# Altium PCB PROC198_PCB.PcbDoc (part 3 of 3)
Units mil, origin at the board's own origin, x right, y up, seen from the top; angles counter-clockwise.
Board outline 858.22 x 1632.74 mil, 4 copper layers (Top Layer, L2_GND1, L3_PWR1, Bottom Layer), stack 54.546 mil thick; 116 components, 64 nets, 355 pads, 1018 vias.

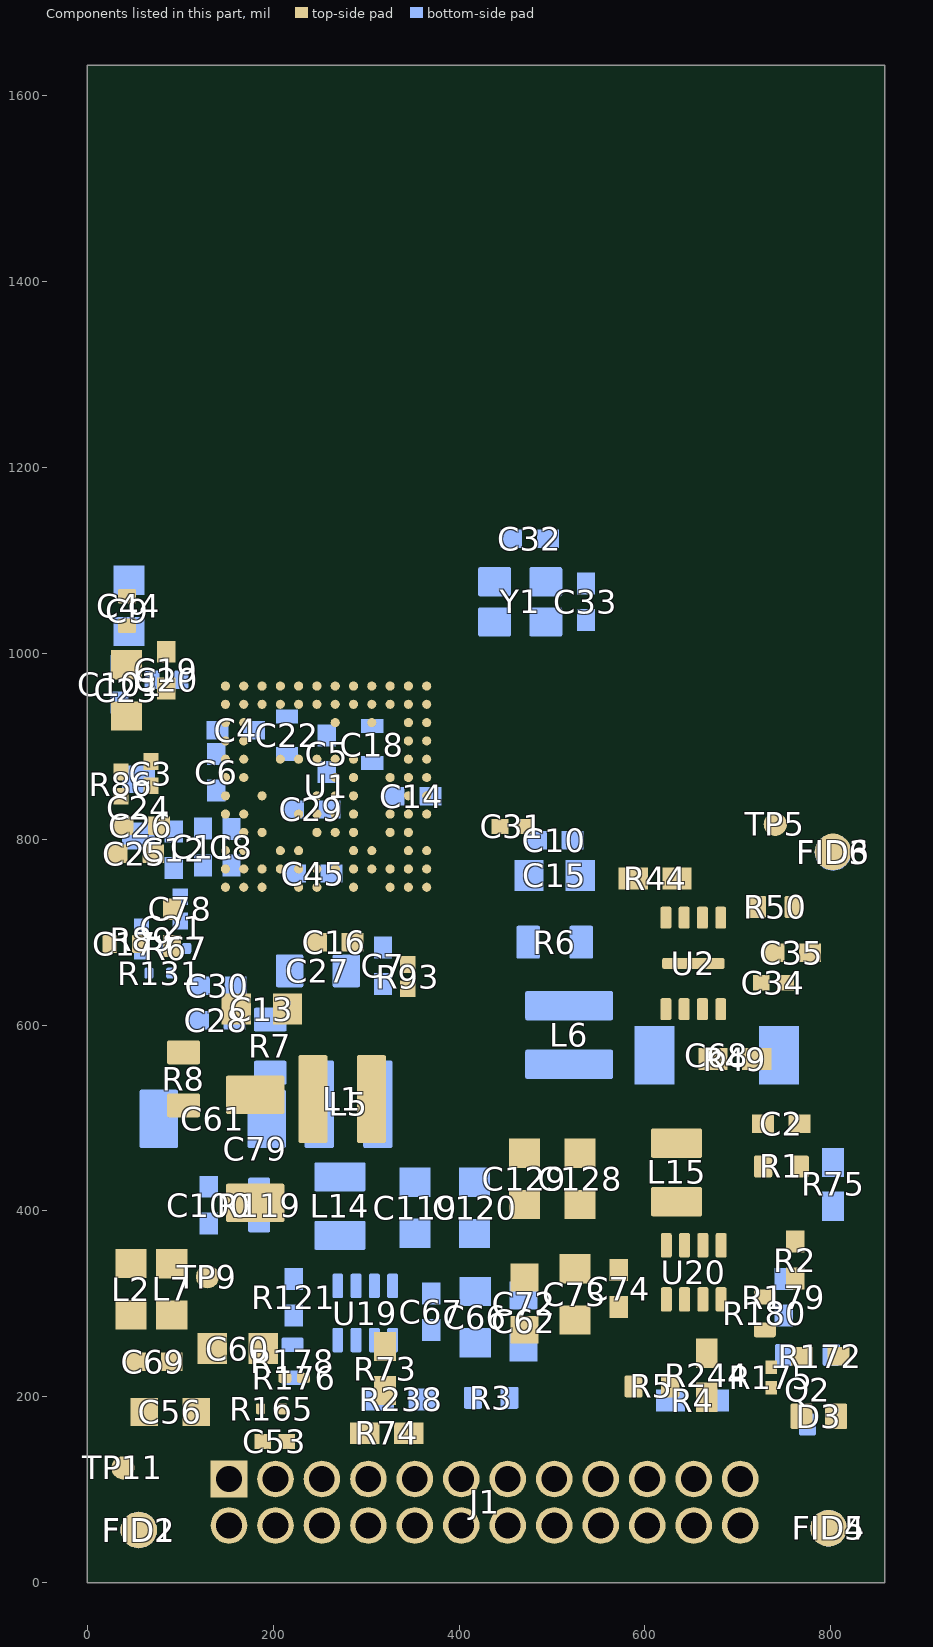
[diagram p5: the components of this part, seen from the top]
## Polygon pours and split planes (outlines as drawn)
RADAR_1V8 on L3_PWR1 "L6_SIGNAL 4-RADAR_1V8" (solid, remove dead copper, pour order 45094): 102.76,857.37 143.9,857.39 143.9,836.13 191.42,836.13 191.19,869.45 278.67,869.45 335.1,812.18 335.1,777.36 496.5,777.38 496.5,820.91 372.75,820.91 313.72,879.94 313.72,921.5 281.71,921.5 270.15,921.5 187.06,921.5 152.34,886.78 102.73,886.78
RADAR_3V3 on L3_PWR1 "RADAR_3V3_L03_P45183" (solid, pour order 45183): 45.3,333.44 45.3,142.85 677.97,142.85 720.43,185.31 720.43,197.8 685.54,198.1 102.68,197.81 89.44,211.06 89.44,336.33
INPUT_3V3 on L3_PWR1 "INPUT_3V3_L03_P45177" (solid, pour order 45177): 101.65,312.42 101.65,269.06 178.91,269.06 234.57,213.4 545.21,213.4 545.21,276.67 769.46,276.67 778.67,267.46 799.44,267.46 799.44,299.14 488.52,299.42 488.52,260 254.87,260 202.45,312.42
GND on L3_PWR1 "GND_L03_P45197" (solid, remove dead copper, pour order 45197): 145.2,679.64 -2.18,827.04 -3.26,825.95 -3.26,-6.44 861.73,-6.44 864.99,-3.18 863.9,-2.1 863.9,679.64
RADAR_1P2_RF on L3_PWR1 "RADAR_1P2_RF_L03_P45169" (solid, pour order 45169): 26.02,951.69 88.85,951.94 117.52,923.27 117.52,900.83 106.05,900.83 68.34,863.13 68.34,814.12 107.21,814.12 106.37,596.31 26.02,596.31
RADAR_1V2 on L3_PWR1 "RADAR_1V2_L03_P45154" (solid, pour order 45154): 82.72,847.61 117.73,847.61 145.54,818.03 201.49,818.03 200.98,867.16 244.66,867.16 244.66,846.88 257.74,833.8 307.39,832.96 314.27,826.08 314.27,717.27 117.73,717.27 119.25,809.17 99.65,828.77 82.72,828.77
RADAR_3V3 on L3_PWR1 "RADAR_3V3_L03_P45196" (solid, pour order 45196): 232.47,642.89 520.26,642.89 520.26,791.73 824.95,791.73 824.95,472.88 737.88,472.88 737.88,561.15 251.33,561.15
GND on L3_PWR1 "Top Layer-GND 4" (solid, remove dead copper, pour order 45082): 123.73,930.67 317.82,930.67 330.1,918.4 328.68,916.98 328.68,876.17 368.74,836.12 853.26,836.12 853.26,1642.81 2.07,1642.81 2.07,1052.34 106.29,948.12
RADAR_3V3 on L3_PWR1 "RADAR_3V3_L03_P45182" (solid, pour order 45182): 135.8,642.12 257.24,642.12 257.24,341 241.43,325.19 45.04,325.19 45.04,385 135.8,385
RADAR_1V2 on L3_PWR1 "RADAR_1V2_L03_P45200" (solid, pour order 45200): 182.5,729.65 116.75,729.65 116.75,668.65 182.5,668.65
RADAR_1V8 on L3_PWR1 "RADAR_1V8_L03_P45181" (solid, pour order 45181): 187.96,710.71 187.96,657 496.8,657 496.8,789.65 496.07,790.38 494.85,789.17 335.1,789.17 335.1,710.71
no net on Bottom Solder "NONET_L01_P-001" (solid): 864.93,1647.45 -2.48,1647.45 -3.34,1646.6 -3.34,1097.02 23.79,1070.7 24.09,1103.49 65.57,1103.49 65.39,1067.38 83.38,1049.39 83.27,988.15 118.44,988.15 118.44,950.2 136,932.64 199.87,932.9 199.87,945.43 229.38,945.43 229.56,932.9 327.04,932.9 329.31,930.64 329.24,877.8 340.97,866.31 383.61,866.31 399.27,850.64 412.64,850.83 424.13,839.28 865.43,839.28
REG_1V2 on Bottom Layer "REG_1V2_L04_P45186" (solid, pour order 45186): 170.48,563.04 222.4,563.04 270.07,563.04 270.07,466.32 270.65,465.74 169.78,465.46
GND on Bottom Layer "GND_L04_P45201" (solid, remove dead copper, pour order 45201): 841.13,821.58 840.02,822.7 2.38,822.7 -1.08,826.16 -2.17,825.08 -2.17,-7.32 862.82,-7.32 866.08,-4.06 865,-2.97 865,817.47
RADAR_1V2 on Bottom Layer "RADAR_1V2_L04_P45185" (solid, pour order 45185): 175.88,709.11 147.33,709.11 127.77,687.97 127.77,667.48 145.95,649.3 145.95,593.81 146.57,593.19 176.5,593.19 182.74,586.95 212.77,586.95 232.83,586.95 232.83,622.35 232.83,678.78 176.41,678.35
GND on Bottom Layer "GND_L04_P45195" (solid, pour order 45195): 268.69,676.76 269.49,677.56 295.91,677.56 295.91,663.15 302.05,657.01 331.67,657.01 331.67,576.42 330.33,575.08 330.07,575.35 283.9,575.35 283.9,614.85 272.42,626.32 268.42,626.32 268.42,677.83 267.62,678.63
RADAR_1P2_RF on Bottom Layer "RADAR_1P2_RF_L04_P45147" (solid, pour order 45147): 21.57,1040.44 65.07,1040.25 65.07,988.77 65.47,988.38 78.42,988.38 78.42,966.1 96.77,947.75 118.27,926.26 118.27,906.24 76.15,863.47 76.15,846.31 14.6,846.31 14.73,887.28 57.96,887.28 70.07,899.39 70.07,947.15 57.11,960.12 47.98,969.24 22.25,969.24
GND on Bottom Layer "Top Layer-GND 4" (solid, remove dead copper, pour order 44948): 31.53,1063.87 68.71,1064.02 83.26,1049.47 82.88,985.83 135.11,933.6 326.27,933.6 329.29,930.57 329.29,878.01 356.51,850.79 412.73,850.79 424.08,839.32 863.05,839.32 863.05,1641.25 -18.97,1641.25 -18.98,1113.78
REG_1V8 on Bottom Layer "REG_1V8_L04_P45190" (solid, pour order 45190): 514.81,708.38 549.2,708.4 548.78,672.32 633.53,672.32 633.53,534.94 585.86,534.94 585.86,589.31 574.97,600.2 463.89,600.2 463.41,600.69 463.41,638.92 511.57,638.92 514.31,641.66
INPUT_3V3 on Bottom Layer "INPUT_3V3_L04_P45193" (solid, pour order 45193): 102.45,307.82 161.25,307.82 161.36,307.29 161.36,269.08 160.72,269.08 150.58,258.94 150.58,156.18 151.11,156.18 176.73,130.56 176.73,84.57 223.68,84.57 223.68,41.67 223.04,42.1 128.7,42.1 128.7,127.27 97.86,158.11 97.86,307.82
RADAR_1V8 on Bottom Layer "RADAR_1V8_L04_P45152" (solid, pour order 45152): 497.7,651.8 497.9,828.46 351.77,828.46 341.41,838.82 341.41,854.23 326.38,869.25 295.37,869.25 295.37,851.09 310.43,836.03 320.09,836.03 354.72,801.4 396.75,802.62 424.09,775.28 424.09,652.59
GND on Bottom Layer "GND_L04_P45167" (solid, pour order 45167): 322.73,392.51 521.24,392.51 521.24,290.53 406.4,290.53 397.24,299.69 352.68,299.44 334.86,281.62 333.62,282.86 252.19,282.86 237.58,268.25 237.58,248.45 209.36,248.45 209.36,300.93 322.73,300.93 322.73,308.31
INPUT_3V3 on Bottom Layer "INPUT_3V3_L04_P45162" (solid, pour order 45162): 303.27,274.41 336.67,274.41 350.54,288.29 387.54,288.29 401.41,274.41 544.57,274.41 544.57,224.57 429.71,224.57 429.71,242.04 322.54,242.04 322.54,202.22 318.69,198.37 293.77,198.37 293.77,224.57 302.76,233.56 302.76,273.9
REG_OUT_1V8 on Bottom Layer "REG_OUT_1V8_L04_P45191" (solid, pour order 45191): 470.37,573.34 565.07,573.34 565.07,495.91 525.01,495.91 480.81,540.1 470.37,540.1
REG_OUT_1V2 on Bottom Layer "REG_OUT_1V2_L04_P45142" (solid, pour order 45142): 375.56,520.28 331.11,563.68 295.98,563.68 295.98,458.91 113.88,458.91 113.88,411.51 218.62,411.51 439.16,411.51 439.16,458.91 376.04,458.91
REG_RF_1V2 on Top Layer "REG_RF_1V2_L01_P45189" (solid, pour order 45189): 81.86,529.65 141.11,529.65 140.88,569.58 209.2,569.58 260.27,569.58 260.27,469.86 222.3,469.86 192.95,499.2 81.86,499.2
GND on Top Layer "GND_L01_P45199" (solid, remove dead copper, pour order 45199): 840.99,809.65 839.87,810.76 2.23,810.76 -1.23,814.22 -2.32,813.14 -2.32,-19.26 862.68,-19.26 865.94,-16 864.85,-14.91 864.85,805.53
RADAR_3V3 on Top Layer "RADAR_3V3_L01_P45194" (solid, pour order 45194): 131.86,319.47 21.62,319.47 21.62,381.07 10.01,395.83 10.26,697.29 35.48,697.29 35.48,676.76 23.96,676.76 23.28,399.07 36.22,385.19 89.97,384.58 89.97,381.07 131.86,339.18
RADAR_1V_RF_OUT on Top Layer "RADAR_1V_RF_OUT_L01_P45157" (solid, pour order 45157): 21.1,1038.12 66.42,1038.12 66.41,980.21 98.28,980.21 98.28,970.83 146.13,930.53 173.74,930.53 173.59,920.24 136.7,920.22 103.78,949.37 74.79,949.64 65.89,957 21.1,957
GND on Top Layer "Top Layer-GND 4" (solid, remove dead copper, pour order 45139): 81.35,1051.28 81.35,1019.94 135.16,966.14 135.16,950.79 148.35,937.56 170.51,937.66 174.01,934.16 187.7,934.16 189.83,932.04 324.92,932.04 324.92,876.14 337.26,863.8 337.19,847.05 343.21,841.03 352.38,841.03 353.48,842.13 353.48,854.78 416.64,854.72 432.79,838.56 849.47,838.56 849.47,1655.32 7.67,1655.32 7.66,1084.07 48.56,1084.07
INPUT_3V3 on Top Layer "INPUT_3V3_L01_P45192" (solid, pour order 45192): 22.92,307.85 161.48,307.85 161.48,269.57 151.03,259.13 151.03,155.79 177.46,129.36 177.46,85.04 224.34,85.04 226.68,82.7 226.68,42 130.79,42 128.45,44.34 128.45,128.49 94.35,162.58 94.35,206.71 73.9,227.17 74.75,228.02 74.75,262.97 68.15,269.57 22.5,269.57
RADAR_1P2_RF on Top Layer "Top Layer-RADAR_1P2_RF" (solid, remove dead copper, pour order 45126): 71.21,936.66 101.81,936.66 125.93,912.54 171.56,912.54 175.13,908.97 175.13,899.26 172.56,896.69 133.66,896.69 88.4,896.69 71.21,913.88
REG_OUT_1V8 on Top Layer "REG_OUT_1V8_L01_P44844" (solid, pour order 44844): 739.41,508.63 739.41,435.71 689.87,435.71 689.87,450.01 563.21,450.01 555.51,442.31 441.15,442.31 441.15,504.78 441.15,536.1 551.6,536.37 551.81,508.02
GND on Top Layer "GND_L01_P45160" (solid, pour order 45160): 773.65,296.71 773.13,297.23 773.13,332.32 709.18,332.32 699.79,341.71 629.29,341.71 629.29,348.8 628.4,349.68 628.4,377.14 627.34,378.2 595.63,378.2 547.8,426.03 426.66,426.03 426.66,313.22 702,313.22 702,304.96 709.89,297.07
RADAR_1P2_RF on Top Layer "RADAR_1P2_RF_L01_P45188" (solid, pour order 45188): 62.44,635.13 62.44,592.16 82.94,592.16 82.94,549.9 123.89,549.9 123.89,600.24 114.09,600.1 98.49,615.7 98.49,635.13
INPUT_3V3 on Top Layer "INPUT_3V3_L01_P45175" (solid, pour order 45175): 647.3,317.89 610.21,317.89 601.29,308.98 545.84,308.98 535.51,298.66 495.79,298.66 495.79,287.53 442.54,287.53 442.54,256.55 474.31,223.42 570.44,223.42 570.44,278.13 574.01,281.69 648.19,281.69 648.91,282.41 648.91,317.72
REG_OUT_1V2 on Top Layer "REG_OUT_1V2_L01_P45163" (solid, pour order 45163): 290.23,571.32 290.89,570.66 345.31,570.66 345.31,465.26 345.64,464.93 290.23,464.93
GND on L2_GND1 "GND_L02_P45198" (solid, pour order 45198): 2.66,1639.42 855.38,1639.42 857.85,1636.95 857.85,0.52 -1.04,0.52

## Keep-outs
Keep-Out Layer:
  text ".Layer_Name" at -1267.26,-2351.64 h60

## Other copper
Top Layer:
  region net TX1: 637.98,1069.92 637.98,1089.61 637.71,1089.61 637.71,1115.79 635.3,1115.79 635.3,1129.53 665.81,1129.53 665.81,1179.96 635.3,1179.96 635.3,1237.2 639.24,1237.2 639.24,1224.71 665.81,1224.71 665.81,1275.14 600.85,1275.14 600.85,1224.71 627.43,1224.71 627.43,1237.2 631.36,1237.2 631.36,1179.96 600.85,1179.96 600.85,1129.53 631.36,1129.53 631.37,1115.79 628.96,1115.79 628.96,1089.61 628.68,1089.61 628.68,1069.92
  region net TX2: 733.19,1069.92 733.19,1089.61 732.92,1089.61 732.92,1115.79 730.51,1115.79 730.51,1129.53 761.02,1129.53 761.02,1179.96 730.51,1179.96 730.51,1237.2 734.45,1237.2 734.45,1224.71 761.02,1224.71 761.02,1275.15 696.06,1275.15 696.06,1224.71 722.64,1224.71 722.64,1237.2 726.58,1237.2 726.58,1179.96 696.06,1179.96 696.06,1129.53 726.58,1129.53 726.58,1115.79 724.17,1115.79 724.17,1089.61 723.89,1089.61 723.89,1069.92
  pour cut-out: 713.81,1077.4 718.59,1072.62 738.51,1072.62 743.05,1077.4 815.72,1077.41 815.72,1334.18 546.16,1334.18 546.16,1077.39 618.91,1077.4 623.37,1072.94 643.3,1072.94 647.69,1077.4
  region net RX1: 136.83,1179.36 136.83,1199.05 136.55,1199.05 136.55,1225.23 134.14,1225.23 134.14,1238.97 164.66,1238.97 164.66,1289.4 134.14,1289.4 134.14,1346.64 138.08,1346.64 138.08,1334.16 164.66,1334.16 164.66,1384.59 99.7,1384.59 99.7,1334.16 126.27,1334.16 126.27,1346.64 130.21,1346.64 130.21,1289.4 99.7,1289.4 99.7,1238.97 130.21,1238.97 130.21,1225.23 127.8,1225.23 127.8,1199.05 127.53,1199.05 127.53,1179.36
  region net RX3: 327.19,1179.36 327.19,1199.05 326.92,1199.05 326.92,1225.23 324.51,1225.23 324.51,1238.97 355.02,1238.97 355.02,1289.4 324.51,1289.4 324.51,1346.64 328.45,1346.64 328.45,1334.16 355.02,1334.16 355.02,1384.59 290.06,1384.59 290.06,1334.16 316.64,1334.16 316.64,1346.64 320.58,1346.64 320.58,1289.4 290.06,1289.4 290.06,1238.97 320.58,1238.97 320.58,1225.23 318.17,1225.23 318.17,1199.05 317.89,1199.05 317.89,1179.36
  region net RX2: 232.01,1274.56 232.01,1294.25 231.73,1294.25 231.73,1320.43 229.33,1320.43 229.33,1334.17 259.84,1334.17 259.84,1384.6 229.33,1384.6 229.33,1441.84 233.26,1441.84 233.26,1429.35 259.84,1429.35 259.84,1479.79 194.88,1479.79 194.88,1429.35 221.45,1429.35 221.45,1441.84 225.39,1441.84 225.39,1384.6 194.88,1384.6 194.88,1334.17 225.39,1334.17 225.39,1320.43 222.99,1320.43 222.99,1294.25 222.71,1294.25 222.71,1274.56
  pour cut-out: 256.78,1234.06 251.87,1238.96 249.64,1238.96 242.22,1238.95 237.32,1234.06 217.37,1234.06 212.45,1238.97 205.48,1238.97 203.41,1238.97 198.5,1234.06 198.51,1176.01 149.71,1176.01 143.52,1169.75 120.06,1169.75 113.79,1176.01 66.2,1176.01 36.85,1205.36 36.85,1442.73 45.64,1442.73 140.39,1537.48 314.84,1537.48 409.71,1442.6 417.87,1442.6 417.87,1176.01 338.9,1176.01 334.03,1171.05 313.28,1171.05 308.32,1176.01 256.78,1176.01
  text ".Layer_Name" at -1252.74,-2340.54 h60
L2_GND1:
  text ".Layer_Name" at -1264.57,-2344.88 h60
L3_PWR1:
  text ".Layer_Name" at -1264.57,-2344.88 h60
Bottom Layer:
  text ".Layer_Name" at -1018.85,-2336.57 h60

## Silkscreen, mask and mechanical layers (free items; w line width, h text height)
Top Overlay:
  text "TEXAS" at 366.05,562.12 h15
  text "INSTRUMENTS" at 368.23,537.12 h15
  text "IWRL6432FSPEVM Rev.B" at 188.37,13.36 h40
  text ".Layer_Name" at -1264.57,-2344.88 h60
Bottom Overlay:
  lines w5: 81.33,706.01 81.33,718.04 ; 107.41,589.88 174.59,589.88
  text "X" at 778.15,621.61 h250
  text "W" at 445.5,553.92 h200
  text "For evaluation only;" at 738.41,471.37 h35
  text "not FCC approved" at 737.97,443.08 h35
  text "for resale." at 738.41,415.08 h35
  text "C" at 682.73,295.19 h200
  text ".Layer_Name" at -1018.85,-2336.57 h25
Top Paste:
  text ".Layer_Name" at -1264.57,-2344.88 h60
Bottom Paste:
  text ".Layer_Name" at -1018.85,-2336.57 h60
Top Solder:
  region: -3.48,1657.96 -3.48,1084.77 49.06,1084.77 81.8,1052.02 81.8,1019.51 98.73,1019.48 98.73,1004.01 118.84,980.71 315.74,980.71 325.76,990.74 341.64,990.74 350.17,999.58 382.96,999.58 420.91,1037.84 420.78,1108.6 414.24,1116.64 414.22,1130.01 424.13,1139.91 438.71,1139.91 448.72,1129.89 448.72,1116.03 442.47,1108.7 442.65,1020.64 512.78,1020.64 519.23,1027.46 530.31,1027.38 539.59,1019.76 539.59,1008.79 532.2,998.95 519.82,998.62 510.33,1008.11 442.62,1008.11 402.62,968.1 374.68,968.11 374.6,855.2 416.04,855.2 432.4,839.26 863.59,839.26 863.59,1657.96
  region: 221.86,981.91 232.95,981.91 232.95,974.84 221.86,974.84
  region: 182.49,981.91 193.58,981.91 193.58,974.84 182.49,974.84
  region: 261.23,981.91 272.32,981.91 272.32,974.84 261.23,974.84
  region: 382.22,891.61 382.22,880.52 375.15,880.52 375.15,891.61
  region: 382.22,930.98 382.22,919.89 375.15,919.89 375.15,930.98
  text ".Layer_Name" at -1264.57,-2344.88 h60
  text ".Layer_Name" at -1264.57,-2344.88 h60
Bottom Solder:
  pour cut-out: 512.11,1143.54 407.22,1143.84 407.22,1036.98 370.64,1000.4 370.64,974.77 435.45,974.77 455.03,994.35 531.07,994.35 554.69,1017.97 554.69,1102.3
  region: 16.85,1077.15 16.47,1077.15 -3.26,1096.88 -3.23,1096.91 -3.23,1632.72 15.8,1632.72 15.97,1632.9
  region: 864.77,1624.61 840.17,1624.61 840.17,839.26 865.46,839.22
  region: 865.04,1647.32 -3.95,1647.32 -4.22,1647.06 -4.22,1617.62 865.17,1617.62
  text ".Layer_Name" at -1018.85,-2336.57 h60
Drill Guide:
  text ".Layer_Name" at -1267.26,-2351.64 h60
M1 Board Outline:
  the board outline again, w2
  text ".Layer_Name" at -1273.87,-2274.95 h40
M2 Board Dimensions:
  text "MILS" at 918.22,1816.07 h60
  text "mm" at -100.52,1691.18 h60 r87.09
  text "mm" at 925.82,1679.29 h60
  text "MILS" at -241.62,1671.69 h60 r90
M3 3D STEP Top:
  text ".Layer_Name" at -1267.26,-2351.64 h60
M4 3D STEP Bottom:
  text ".Layer_Name" at -1267.26,-2351.64 h60
M5 Assembly Top:
  lines w10: -2136.26,-2423.31 4463.74,-2423.31 ; -2136.26,-2219.98 4465.74,-2219.98 ; -2136.26,-2016.65 -2136.26,-2626.65 1868.74,-2626.65 4465.74,-2626.65 4465.74,-2016.65 -2135.76,-2016.65 -2135.76,-2626.65 -560.26,-2626.65 ; 328.74,-2626.65 328.74,-2016.65 ; 1595.74,-2219.98 1595.74,-2016.65 ; 2435.74,-2219.98 2435.74,-2016.65 ; 3057.74,-2633.15 3057.74,-2430.31
  text "COMPONENTS MARKED 'DNP' SHOULD NOT BE POPULATED." at -1013.01,2097.18 h60
  text "ASSEMBLY VARIANT:" at -1013.51,1981.68 h60
  text ".VariantName" at 22.49,1981.68 h60
  text "PCB VIEWED FROM TOP SIDE" at -2072.76,-2148.81 h60
  text "BOARD #:" at 403.74,-2148.81 h60
  text ".PRJ_Number" at 949.24,-2148.81 h60
  text "REV:" at 1793.74,-2148.81 h60
  text ".PCB_Rev" at 2085.24,-2148.81 h60
  text "SVN REV:" at 2631.74,-2148.81 h60
  text ".VersionControl_RevNumber" at 3137.74,-2148.81 h60
  text "Assembly Layer Top" at -1277.26,-2348.15 h60
  text "TID #:" at 403.74,-2352.15 h60
  text ".TID" at 949.24,-2352.15 h60
  text "PLOT NAME =" at -2072.76,-2557.48 h60
  text ".plot_File_Name" at -1267.26,-2557.48 h60
  text "GENERATED    :" at 405.74,-2557.48 h60
  text ".Print_Date" at 1275.24,-2557.48 h60
  text ".Print_Time" at 2004.24,-2557.48 h60
  text "TEXAS INSTRUMENTS" at 3268.74,-2557.48 h60
M6 Assembly Bottom:
  lines w10: -2136.76,-2220.48 4465.24,-2220.48 ; -2134.76,-2423.81 4465.24,-2423.81 ; -728.76,-2633.65 -728.76,-2430.81 ; -106.76,-2220.48 -106.76,-2017.15 ; 733.24,-2220.48 733.24,-2017.15 ; 2000.24,-2627.15 2000.24,-2017.15 ; 2889.24,-2627.15 4464.74,-2627.15 4464.74,-2017.15 -2136.76,-2017.15 -2136.76,-2627.15 460.24,-2627.15 4465.24,-2627.15 4465.24,-2017.15
  text "COMPONENTS MARKED 'DNP' SHOULD NOT BE POPULATED." at 4462.31,-1794.1 h60
  text ".VariantName" at 3418.31,-1910.1 h60
  text "ASSEMBLY VARIANT:" at 4457.31,-1910.1 h60
  text ".VersionControl_RevNumber" at -808.76,-2149.31 h60
  text "SVN REV:" at -302.76,-2149.31 h60
  text ".PCB_Rev" at 243.74,-2149.31 h60
  text "REV:" at 535.24,-2149.31 h60
  text ".PRJ_Number" at 1379.74,-2149.31 h60
  text "BOARD #:" at 1925.24,-2149.31 h60
  text "PCB VIEWED FROM BOTTOM SIDE" at 4401.74,-2149.31 h60
  text "Assembly Bottom Layer" at 4040.74,-2338.15 h60
  text ".TID" at 1379.74,-2352.65 h60
  text "TID #:" at 1925.24,-2352.65 h60
  text "TEXAS INSTRUMENTS" at -939.76,-2557.98 h60
  text ".Print_Time" at 324.74,-2557.98 h60
  text ".Print_Date" at 1053.74,-2557.98 h60
  text "GENERATED    :" at 1923.24,-2557.98 h60
  text ".plot_File_Name" at 3596.24,-2557.98 h60
  text "PLOT NAME =" at 4401.74,-2557.98 h60
M7 LPKF Text Top:
  lines w2: 163.61,720.01 195.09,720.01 ; 171.48,720.01 187.22,720.01 ; 179.35,704.27 179.35,735.75 ; 179.35,712.14 179.35,727.88
M9 Title Sheet:
  lines w10: 164.24,-2826.65 164.24,-2626.65 ; 164.24,6473.35 164.24,6673.35 ; 2664.24,-2826.65 2664.24,-2626.65 ; 2664.24,6473.35 2664.24,6673.35
  text "1" at -1104.43,6543.35 h70
  text "2" at 1391.24,6543.35 h70
  text ".Layer_Name" at -1257.96,-2358.63 h60
  text "1" at -1104.43,-2756.65 h70
  text "2" at 1391.24,-2756.65 h70
M10 Fab Notes:
  drawing of 251 lines, arcs and shapes, not listed
  text "3" at 3880.58,6543.35 h70
  text "4" at 6387.25,6543.35 h70
  text "5" at 8886.24,6543.35 h70
  text "6" at 11391.24,6543.35 h70
  text "A" at -2260.76,5400.35 h70
  text "A" at 12539.24,5400.35 h70
  text "DESIGN INFORMATION" at 10537.75,4863.03 h60
  text "3.9" at 10932.23,4733.63 h60
  text "MIN. TRACK WIDTH:" at 9893.2,4730.9 h60
  text "MIL" at 11144.2,4730.9 h60
  text "3.9" at 10929.69,4614.25 h60
  text "MIN. CLEARANCE:" at 9893.2,4606.77 h60
  text "MIL" at 11144.2,4606.77 h60
  text "MIN. VIA PAD SIZE:" at 9893.2,4482.65 h60
  text "18" at 10915.88,4475.28 h60
  text "MIL" at 11166.74,4473.85 h60
  text "EXTERNAL" at 11414.34,4355.34 h60
  text "0.127mm (5.0MIL)" at 10588.2,4352.75 h60
  text "MINIMUM ANNULAR RING" at 9563.96,4344.53 h60
  text "PER" at 9763.96,4234.4 h60
  text "IPC-D-275 CLASS 2 LEVEL C" at 9983.96,4234.4 h60
  text "MIL, HOLES" at 11472.2,4133.92 h60
  text "+/-" at 11079.74,4125.34 h60
  text "+/-" at 11933.74,4125.34 h60
  text "REGISTRATION TOLERANCES:" at 9563.96,4124.27 h60
  text "METAL" at 10763.74,4124.27 h60
  text "5" at 11339.94,4124.27 h60
  text "3" at 12172.94,4124.27 h60
  text "MIL" at 12289.2,4124.27 h60
  text "HOLE SIZE TOLERANCE (UNLESS OTHERWISE SPECIFIED):" at 9563.96,4025.96 h60
  text "+/-" at 11933.74,4023.08 h60
  text "3" at 12172.94,4022.02 h60
  text "MIL" at 12289.2,4022.02 h60
  text "MATERIAL:" at 9489.2,3884.37 h60
  text "FR-4 High Tg" at 10475.64,3755.85 h60
  text "X" at 11217.74,3750.85 h60
  text "REFER STACK-UP" at 11718.59,3750.26 h55
  text "FR-408" at 9910.2,3743.34 h60
  text "OTHER" at 11398.2,3743.34 h60
  text "X" at 11388.74,3602.86 h60
  text "62 MIL (1.6mm) +/-10%" at 10230.3,3600.31 h60
  text "59 MIL +/-10%" at 11810.74,3593.85 h45
  text "THICKNESS:" at 9563.96,3592.09 h60
  text "OTHER" at 11515.2,3592.09 h60
  text "TOLERANCE:" at 9563.96,3453.78 h60
  text "X" at 10412.2,3453.78 h60
  text "ANSI IPC-6012 TYPE 3 CLASS 2" at 10590.21,3453.78 h60
  text "OTHER +/-" at 10590.2,3309.59 h60
  text "BOW & TWIST:" at 9563.96,3164.4 h60
  text "X" at 10412.2,3164.4 h60
  text "ANSI IPC-6012 TYPE 3 CLASS 2" at 10590.21,3164.4 h60
  text "B" at -2260.76,3020.35 h70
  text "B" at 12539.24,3020.35 h70
  text "OTHER +/-" at 10590.2,3017.7 h60
  text "DRILLING:" at 9489.2,2887.08 h60
  text "NC_DRILL FILES" at 11250.2,2781.89 h60
  text "REFERENCE:" at 9563.96,2777.96 h60
  text "X" at 10221.2,2777.86 h60
  text "AS SHOWN" at 10399.2,2777.96 h60
  text "X" at 11122.2,2777.96 h60
  text "OTHER" at 11548.2,2635.7 h60
  text "PTH COPPER THICKNESS:" at 9563.64,2632.18 h60
  text "X" at 10702.88,2632.18 h60
  text "20-30 um" at 10830.87,2632.18 h60
  text "NOTES:" at 2136.8,2578.1 h60
  text "BOARD FINISH:" at 9489.2,2484.58 h60
  text "1. BOARD SHALL MEET THE REQUIREMENTS OF UL-796E WITH FLAMMABILITY RATING OF MINIMUM 94V-0. UL LOGO," at 2163.55,2432.27 h60
  text "SILKSCREEN:" at 9644.42,2374.45 h60
  text "X" at 10602.2,2374.45 h60
  text "TOP" at 10719.2,2374.45 h60
  text "X" at 11112.2,2374.45 h60
  text "BOTTOM" at 11230.2,2374.45 h60
  text "MANUFACTURER'S IDENTIFICATION AND DATE CODE LETTER SHALL BE RENDERED IN SILKSCREEN." at 2270.28,2333.27 h60
  text "SILKSCREEN COLOR:" at 9644.42,2219.26 h60
  text "X" at 10601.2,2219.26 h60
  text "WHITE" at 10719.2,2219.26 h60
  text "OTHER" at 11230.2,2219.26 h60
  text "2. VENDOR MAY ADJUST SOLDERMASK WHEREVER SOLDERMASK PADS ARE THE SAME SIZE (1:1) AS PER THE MANUFACTURING CAPABILITIES" at 2156.57,2207.49 h60
  text "AND ALL OTHER SOLDER MASK PADS SHALL NOT BE MODIFIED, PROVIDED NO ADJACENT COPPER IS EXPOSED AND NO CONFLICT IS PRODUCED" at 2263.3,2108.49 h60
  text "GREEN" at 10850.2,2075.82 h60
  text "X" at 11324.2,2075.82 h60
  text "OTHER" at 11468.2,2075.82 h60
  text "RED" at 11840.74,2075.82 h60
  text "SOLDER RESIST COLOR:" at 9644.42,2068.95 h60
  text "WITH ANY STATED \"VIA TENTING/COVERING\" REQUIREMENTS." at 2263.3,2015.21 h60
  text "MATTE" at 10850.2,1921.56 h60
  text "SEMI-GLOSS" at 11467.74,1920.93 h60
  text "X" at 11323.8,1918.87 h60
  text "3. MANUFACTURER'S IDENTIFICATION,DATECODE LETTER SHALL BE SILKSCREENED ON SOLDER SIDE OF THE BOARD." at 2160.24,1897.11 h60
  text "4. TRACE WIDTH SHOULD BE ACCURATELY ETCHED. MAX TOLERANCE +/- 1 MIL." at 2155.29,1760.78 h60
  text "IMMERSION GOLD (ENIG)" at 10550.2,1748.79 h60
  text "ENEPIG" at 11887.74,1741.57 h60
  text "SURFACE FINISH:" at 9489.2,1740.57 h60
  text "5. LAYER TO LAYER REGISTRATION SHALL BE WITHIN +/-2 MIL." at 2162.35,1636.67 h60
  text "IMM. SILVER" at 11665.12,1612.93 h60
  text "IMM. TIN/SILVER OR EQUIV" at 9818.74,1603.26 h60
  text "X" at 11072.62,1600.57 h60
  text "OTHER" at 11250.2,1599.32 h60
  text "6. REFER IMPEDANCE TABLE FOR IMPEDANCE CONTROL TRACES ON LAYER 1." at 2153.38,1515.8 h60
  text "ARRAY/PANEL:" at 9489.2,1443.94 h60
  text "CUT AND TRIM PER M1 BOARD OUTLINE" at 10550.2,1435.72 h60
  text "7. FOR ACCURACY OF THE ANTENNA DIMENSION, NEED TO BE MEASURE THE  ANTENNA DIMENSIONS ON ONE BOARD" at 2151.19,1364.04 h60
  text "N.C. ROUTE" at 10550.2,1299.75 h60
  text "V. SCORE" at 11416.2,1299.75 h60
  text "X" at 11233.19,1293.81 h60
  text "8. ALL VIAS ARE TENTED ON BOTH SIDES UNLESS OTHERWISE SOLDER MASK OPENED IN GERBER." at 2144.77,1251.36 h60
  text "CERTIFICATION:" at 9489.2,1170.63 h60
  text "MATERIALS AND WORKMANSHIP FOR ALL PCBS" at 10214.2,1170.63 h60
  text "9. VIA HOLE OFFSET SHALL BE WITHIN 1MILS OF ITS ORIGINAL LOCATION" at 2148.7,1135.75 h60
  text "TO MEET OR EXCEED THE REQUIREMENTS OF:" at 10214.2,1076.56 h60
  text "10. FILES ARE IN UNITS OF INCHES (MILS)" at 2135.44,996.78 h60
  text "X" at 9851.7,947.93 h60
  text "ANSI IPC-A-600F CLASS ->" at 9979.7,947.93 h60
  text "X" at 11627.7,947.93 h60
  text "2" at 11737.7,947.93 h60
  text "1" at 11422.7,946.44 h60
  text "3" at 12091.7,946.44 h60
  text "11. UPPER AND LEFTMOST BOARD DIMENSIONS ARE IN MILS, OTHER BOARD SIZE DIMENSIONS ARE IN MM" at 2138.26,877.27 h60
  text "X" at 10663.7,800.25 h60
  text "RoHS" at 10791.7,800.25 h60
  text "OTHER" at 11436.1,800.25 h60
  text "PER ORDER" at 11833.16,800.25 h60
  text "ALL BOARDS MUST MEET OR EXCEED UL94-V0 REQUIREMENTS." at 9516.74,646.42 h60
  text "C" at -2260.76,645.35 h70
  text "C" at 12539.24,645.35 h70
  text "PCB MUST BEAR THE UL94V-0 UL REGISTERED MATERIAL ID NUMBER" at 9516.74,530.36 h60
  text "ADDITIONAL REQUIREMENTS:" at 9489.2,360.93 h60
  text "MICROSECTION:" at 9563.96,253.81 h60
  text "YES" at 10469.7,253.81 h60
  text "REQUIRED" at 11331.2,109.47 h60
  text "BARE BOARD ELEC. TEST:" at 9563.96,106.62 h60
  text "NONE" at 10869.7,106.62 h60
  text "X" at 11213.2,106.62 h60
  text "PER ORDER" at 11923.2,106.62 h60
  text "XX MIL VIAS REQUIRE NON-CONDUCTIVE FILL AND PLANARIZE" at 9747.74,-39.15 h59
  text "XX MIL VIAS REQUIRE CONDUCTIVE FILL AND PLANARIZE" at 9738.74,-198.15 h60
  text "OUTER XX MIL TRACES REQUIRE 50 OHM SINGLE-ENDED IMPEDANCE" at 9733.88,-341.05 h58
  text "LAYER 1 & 6 (INNER LAYERS) XX MIL WIDE, XX MIL SPACE / TRACES REQUIRE 100 OHM DIFFERENTIAL IMPEDANCE" at 9772.74,-591.15 h60
  text "PROJECT TITLE:" at 9499.24,-1215.65 h45
  text ".PRJ_Title" at 9549.24,-1348.97 h70
  text "DESIGNED FOR:" at 9499.24,-1516.65 h45
  text ".PRJ_Customer" at 9549.24,-1656.65 h70
  text "D" at -2260.76,-1724.65 h70
  text "D" at 12539.24,-1724.65 h70
  text "FILE NAME:" at 9499.24,-1816.65 h45
  text ".PCB_File_Name_No_Path" at 9549.24,-1936.65 h70
  text "Texas Instruments (TI) and/or its licensors do not warrant the accuracy or completeness of this specification" at 4529.74,-2098.49 h45
  text "ENGINEER:" at 9499.24,-2106.65 h45
  text "LAYOUT BY:" at 11004.24,-2106.65 h45
  text "or any information contained therein. TI and/or its licensors do not warrant that this design will meet" at 4484.75,-2211.15 h45
  text ".PRJ_Engineer" at 9549.24,-2261.64 h70
  text ".PCB_Layout" at 11054.74,-2261.64 h70
  text "the specifications, will be suitable for your application or fit for any particular purpose, or will operate in" at 4484.75,-2323.82 h45
  text ".Layer_Name" at -1257.96,-2358.63 h60
  text "ALTIUM DESIGNER VERSION:" at 11004.24,-2416.65 h45
  text "an implementation. TI and/or its licensors do not warrant that the design is production worthy. You should" at 4484.75,-2436.48 h45
  text "completely validate and test your design implementation to confirm the system functionality for your application." at 4529.74,-2549.15 h45
  text ".print_Scale" at 9549.24,-2549.97 h70
  text ".Application_BuildNumber" at 11054.74,-2549.97 h70
  text "3" at 3880.58,-2756.65 h70
  text "4" at 6387.25,-2756.65 h70
  text "5" at 8886.24,-2756.65 h70
  text "6" at 11240.42,-2767 h70
M11 Gerber Information:
  lines w10: -2136.26,-2423.31 4463.74,-2423.31 ; -2136.26,-2219.98 4465.74,-2219.98 ; -2136.26,-2016.65 -2136.26,-2626.65 1868.74,-2626.65 4465.74,-2626.65 4465.74,-2016.65 -2135.76,-2016.65 -2135.76,-2626.65 -560.26,-2626.65 ; 328.74,-2626.65 328.74,-2016.65 ; 1595.74,-2219.98 1595.74,-2016.65 ; 2435.74,-2219.98 2435.74,-2016.65 ; 3057.74,-2633.15 3057.74,-2430.31
  text "ALL ARTWORK VIEWED FROM TOP SIDE" at -2072.76,-2148.81 h60
  text "BOARD #:" at 403.74,-2148.81 h60
  text ".PRJ_Number" at 949.24,-2148.81 h60
  text "REV:" at 1793.74,-2148.81 h60
  text ".PCB_Rev" at 2085.24,-2148.81 h60
  text "SVN REV:" at 2631.74,-2148.81 h60
  text ".VersionControl_RevNumber" at 3137.74,-2148.81 h60
  text "LAYER NAME =" at -2072.76,-2351.64 h60
  text "TID #:" at 403.74,-2352.15 h60
  text ".TID" at 949.24,-2352.15 h60
  text "PLOT NAME =" at -2072.76,-2557.48 h60
  text ".plot_File_Name" at -1267.26,-2557.48 h60
  text "GENERATED    :" at 405.74,-2557.48 h60
  text ".Print_Date" at 1275.24,-2557.48 h60
  text ".Print_Time" at 2004.24,-2557.48 h60
  text "TEXAS INSTRUMENTS" at 3268.74,-2557.48 h60
M12 Stackup:
  drawing of 316 lines, arcs and shapes, not listed
  text "NOTE :" at 5742.51,5800.49 h60
  text "1. THIS IS AN IMPEDANCE CONTROLLED BOARD." at 5926.02,5695.46 h60
  text "2. EXTERNAL LAYER CU THICKNESSES ARE FINISHED THICKNESS AFTER PLATING." at 5926.02,5597.59 h60
  text "6" at 7810.15,5434.9 h60
  text "IMPEDANCE TABLE :" at 6653.76,5419.52 h80
  text "LAYER" at 6152.01,5310.17 h70
  text "TRACE WIDTH" at 6439.21,5309.32 h70
  text "SPACING" at 6924.21,5309.32 h70
  text "IMPEDANCE +/- 10%" at 7259.21,5309.32 h70
  text "REFERENCE LAYER" at 7984.21,5309.32 h70
  text "TOP" at 6219.09,5151.18 h70
  text "9.3 MILS" at 6504.09,5146.18 h65
  text "5.3 MILS" at 6959.09,5146.18 h65
  text "50 OHM" at 7379.09,5146.18 h65
  text "LAYER-2 (GND LAYER)" at 7944.09,5146.18 h65
  text "LAYER STACK-UP :" at 2143.04,575.05 h80
  text "Layer" at 2175.41,411.49 h60
  text "Name" at 2585.32,411.49 h60
  text "Material" at 3515.06,411.49 h60
  text "Thickness" at 6394.18,411.49 h60
  text "Constant" at 7044.01,411.49 h60
  text "Board Layer Stack" at 7613.87,411.49 h60
  text "Top Overlay" at 2585.32,291.49 h60
  text "Top Solder" at 2585.32,171.49 h60
  text "Solder Resist" at 3515.06,171.49 h60
  text "0.80mil" at 6394.18,171.49 h60
  text "3.2" at 7044.01,171.49 h60
  text "1" at 2175.41,51.49 h60
  text "Top Layer" at 2585.32,51.49 h60
  text "1.38mil" at 6394.18,51.49 h60
  text "Dielectric 1" at 2585.32,-68.51 h60
  text "Isola FR408HR (DUAL PLY, 2x1067, SPREAD GLASS )" at 3515.06,-68.51 h60
  text "5.00mil" at 6394.18,-68.51 h60
  text "3.3" at 7044.01,-68.51 h60
  text "2" at 2175.41,-188.51 h60
  text "L2_GND1" at 2585.32,-188.51 h60
  text "1.20mil" at 6394.18,-188.51 h60
  text "Dielectric 4" at 2585.32,-308.51 h60
  text "Isola FR408HR (DUAL PLY, 2x1067, SPREAD GLASS )" at 3515.06,-308.51 h60
  text "39.39mil" at 6394.18,-308.51 h60
  text "4.28" at 7044.01,-308.51 h60
  text "3" at 2175.41,-428.51 h60
  text "L3_PWR1" at 2585.32,-428.51 h60
  text "1.20mil" at 6394.18,-428.51 h60
  text "Dielectric 3" at 2585.32,-548.51 h60
  text "Isola FR408HR (DUAL PLY, 2x1067, SPREAD GLASS )" at 3515.06,-548.51 h60
  text "5.00mil" at 6394.18,-548.51 h60
  text "3.79" at 7044.01,-548.51 h60
  text "4" at 2175.41,-668.51 h60
  text "Bottom Layer" at 2585.32,-668.51 h60
  text "1.38mil" at 6394.18,-668.51 h60
  text "Bottom Solder" at 2585.32,-788.51 h60
  text "Solder Resist" at 3515.06,-788.51 h60
  text "0.80mil" at 6394.18,-788.51 h60
  text "3.2" at 7044.01,-788.51 h60
  text "Bottom Overlay" at 2585.32,-908.51 h60
  text ".Layer_Name" at -1267.26,-2351.64 h60
M13 Component Bodies Top:
  text ".Layer_Name" at -1267.26,-2351.64 h60
M14 Component Bodies Bottom:
  text ".Layer_Name" at -1267.26,-2351.64 h60
M15 Courtyards Top:
  text ".Layer_Name" at -1267.26,-2351.64 h60
M16 Courtyards Bottom:
  text ".Layer_Name" at -1267.26,-2351.64 h60
Drill Drawing:
  circle w10: c-1749.56,4027.7 r33.33
  circle w10: c-1804.56,3222.14 r33.33
  lines w10: -1837.9,3105.47 -1771.23,3105.47 -1804.56,3038.8 -1837.9,3105.47 ; -1782.89,3911.03 -1716.22,3911.03 -1749.56,3844.36 -1782.89,3911.03
  lines w15: -1897.69,2993.8 9233.2,2993.8 ; -1897.69,3293.8 9233.2,3293.8 ; -1842.68,3799.36 4541.55,3799.36 ; -1842.68,4099.36 4541.55,4099.36 ; -1346.81,2843.8 -1346.81,3443.8 ; -1291.81,3649.36 -1291.81,4249.36 ; -696.99,2843.8 -696.99,3443.8 ; -641.98,3649.36 -641.98,4249.36 ; 402.69,2843.8 402.69,3443.8 ; 457.7,3649.36 457.7,4249.36 ; 908.57,2843.8 908.57,3443.8 ; 963.57,3649.36 963.57,4249.36 ; 1642.37,2843.8 1642.37,3443.8 ; 2297.18,3649.36 2297.18,4249.36 ; 3141.92,2843.8 3141.92,3443.8 ; 3630.79,3649.36 3630.79,4249.36 ; 3731.77,2843.8 3731.77,3443.8 ; 4477.57,2843.8 4477.57,3443.8 ; 5667.22,2843.8 5667.22,3443.8 ; 6520.98,2843.8 6520.98,3443.8 ; 7854.59,2843.8 7854.59,3443.8 ; -1897.69,2843.8 9233.2,2843.8 9233.2,3443.8 -1897.69,3443.8 -1897.69,2843.8 ; -1842.68,3649.36 4541.55,3649.36 4541.55,4249.36 -1842.68,4249.36 -1842.68,3649.36
  text "Symbol" at -1752.68,4144.36 h72
  text "Count" at -1246.81,4144.36 h72
  text "Hole Size" at -596.98,4144.36 h72
  text "Plated" at 502.7,4144.36 h72
  text "Hole Tolerance (+)" at 1008.57,4144.36 h72
  text "Hole Tolerance (-)" at 2342.18,4144.36 h72
  text "Hole Length" at 3675.79,4144.36 h72
  text "24" at -1246.81,3994.36 h60
  text "27.56mil (0.700mm)" at -596.98,3994.36 h60
  text "PTH" at 502.7,3994.36 h60
  text "-" at 3675.79,3994.36 h60
  text "1018" at -1246.81,3844.36 h60
  text "8.00mil (0.203mm)" at -596.98,3844.36 h60
  text "PTH" at 502.7,3844.36 h60
  text "3.00mil (0.076mm)" at 1008.57,3844.36 h60
  text "3.00mil (0.076mm)" at 2342.18,3844.36 h60
  text "-" at 3675.79,3844.36 h60
  text "1042 Total" at -1246.81,3694.36 h60
  text "Symbol" at -1807.69,3338.8 h72
  text "Count" at -1301.81,3338.8 h72
  text "Hole Size" at -651.99,3338.8 h72
  text "Plated" at 447.69,3338.8 h72
  text "Hole Type" at 953.57,3338.8 h72
  text "Drill Layer Pair" at 1687.37,3338.8 h72
  text "Via/Pad" at 3186.92,3338.8 h72
  text "Pad Shape" at 3776.77,3338.8 h72
  text "Template" at 4522.57,3338.8 h72
  text "Description" at 5712.22,3338.8 h72
  text "Hole Tolerance (+)" at 6565.98,3338.8 h72
  text "Hole Tolerance (-)" at 7899.59,3338.8 h72
  text "24" at -1301.81,3188.8 h60
  text "27.56mil (0.700mm)" at -651.99,3188.8 h60
  text "PTH" at 447.69,3188.8 h60
  text "Round" at 953.57,3188.8 h60
  text "Top Layer - Bottom Layer" at 1687.37,3188.8 h60
  text "Pad" at 3186.92,3188.8 h60
  text "(Mixed)" at 3776.77,3188.8 h60
  text "(Mixed)" at 4522.57,3188.8 h60
  text "1018" at -1301.81,3038.8 h60
  text "8.00mil (0.203mm)" at -651.99,3038.8 h60
  text "PTH" at 447.69,3038.8 h60
  text "Round" at 953.57,3038.8 h60
  text "Top Layer - Bottom Layer" at 1687.37,3038.8 h60
  text "Via" at 3186.92,3038.8 h60
  text "Rounded" at 3776.77,3038.8 h60
  text "v46h20m0mx0(Tol8-8)" at 4522.57,3038.8 h60
  text "3.00mil (0.076mm)" at 6565.98,3038.8 h60
  text "3.00mil (0.076mm)" at 7899.59,3038.8 h60
  text "1042 Total" at -1301.81,2888.8 h60
  text ".Layer_Name" at -1267.26,-2351.64 h60
M17 Embedded Cavity:
  text ".Layer_Name" at -1267.26,-2351.64 h60
M18 Embedded Assembly:
  text ".Layer_Name" at -1252.74,-2340.54 h60
M19 Embedded Keepout:
  text ".Layer_Name" at -1164.78,-2348.54 h60
TX:
  lines w0.5: 600.85,1129.53 600.85,1179.96 665.81,1179.96 665.81,1129.53 600.85,1129.53 ; 600.85,1224.71 600.85,1275.14 665.81,1275.14 665.81,1224.71 639.24,1224.71 639.24,1237.15 627.43,1237.15 627.43,1224.71 600.85,1224.71 ; 628.68,1069.92 628.68,1089.61 637.98,1089.61 637.98,1069.92 628.68,1069.92 ; 628.96,1089.61 628.96,1115.79 637.71,1115.79 637.71,1089.61 628.96,1089.61 ; 631.36,1115.79 631.36,1142.36 635.3,1142.36 635.3,1115.79 631.36,1115.79 ; 631.36,1179.96 631.36,1275.14 635.3,1275.14 635.3,1179.96 631.36,1179.96 ; 696.06,1129.53 696.06,1179.96 761.02,1179.96 761.02,1129.53 696.06,1129.53 ; 696.06,1224.71 696.06,1275.15 761.02,1275.15 761.02,1224.71 734.45,1224.71 734.45,1237.15 722.64,1237.15 722.64,1224.71 696.06,1224.71 ; 723.89,1069.92 723.89,1089.61 733.19,1089.61 733.19,1069.92 723.89,1069.92 ; 724.17,1089.61 724.17,1115.79 732.92,1115.79 732.92,1089.61 724.17,1089.61 ; 726.58,1115.79 726.58,1142.36 730.51,1142.36 730.51,1115.79 726.58,1115.79 ; 726.58,1179.96 726.58,1275.15 730.51,1275.15 730.51,1179.96 726.58,1179.96
RX:
  lines w0.5: 99.7,1238.97 99.7,1289.4 164.66,1289.4 164.66,1238.97 134.14,1238.97 134.14,1225.23 130.21,1225.23 130.21,1238.97 99.7,1238.97 ; 99.7,1334.16 99.7,1384.59 164.66,1384.59 164.66,1334.16 138.08,1334.16 138.08,1346.6 126.27,1346.6 126.27,1334.16 99.7,1334.16 ; 127.53,1179.36 127.53,1199.05 136.83,1199.05 136.83,1179.36 127.53,1179.36 ; 127.8,1199.05 127.8,1225.23 136.55,1225.23 136.55,1199.05 127.8,1199.05 ; 130.21,1289.4 130.21,1384.59 134.14,1384.59 134.14,1289.4 130.21,1289.4 ; 194.88,1334.17 225.39,1334.17 225.39,1320.43 229.33,1320.43 229.33,1334.17 259.84,1334.17 259.84,1384.6 194.88,1384.6 194.88,1334.17 ; 194.88,1429.35 221.45,1429.35 221.45,1441.79 233.27,1441.79 233.27,1429.35 259.84,1429.35 259.84,1479.79 194.88,1479.79 194.88,1429.35 ; 222.71,1274.56 232.01,1274.56 232.01,1294.25 222.71,1294.25 222.71,1274.56 ; 222.99,1294.25 231.73,1294.25 231.73,1320.43 222.99,1320.43 222.99,1294.25 ; 225.39,1384.6 229.33,1384.6 229.33,1479.79 225.39,1479.79 225.39,1384.6 ; 290.06,1238.97 320.58,1238.97 320.58,1225.23 324.51,1225.23 324.51,1238.97 355.02,1238.97 355.02,1289.4 290.06,1289.4 290.06,1238.97 ; 290.06,1334.16 316.64,1334.16 316.64,1346.6 328.45,1346.6 328.45,1334.16 355.02,1334.16 355.02,1384.59 290.06,1384.59 290.06,1334.16 ; 317.89,1179.36 327.19,1179.36 327.19,1199.05 317.89,1199.05 317.89,1179.36 ; 318.17,1199.05 326.92,1199.05 326.92,1225.23 318.17,1225.23 318.17,1199.05 ; 320.58,1289.4 324.51,1289.4 324.51,1384.59 320.58,1384.59 320.58,1289.4
fanoutbga:
  drawing of 565 lines, arcs and shapes, not listed
PCB_dimesnion_airgap_trace_width:
  lines w0.5: 150.59,923.51 150.59,964.84 ; 150.59,923.51 150.59,1004.21 ; 150.59,923.51 150.59,1004.21 ; 150.59,923.51 315.94,923.51 ; 150.59,923.51 315.94,923.51 ; 150.59,923.51 315.94,923.51 ; 150.59,964.84 187.99,964.84 ; 150.59,964.84 187.99,964.84 ; 150.59,964.84 150.59,1004.21 ; 150.59,1004.21 150.59,924.09 315.94,924.09 315.94,1004.21 ; 150.59,1004.21 315.94,1004.21 ; 150.59,1004.21 315.94,1004.21 ; 150.59,1004.21 315.94,1004.21 ; 150.59,1004.21 315.94,1004.21 ; 187.99,964.84 ccw(c187.99,964.84) 187.99,964.84 ; 187.99,964.84 ccw(c187.99,964.84) 187.99,964.84 ; 187.99,964.84 ccw(c187.99,964.84) 187.99,964.84 ; 187.99,964.84 227.36,964.84 ; 187.99,964.84 227.36,964.84 ; 227.36,964.84 ccw(c227.36,964.84) 227.36,964.84 ; 227.36,964.84 ccw(c227.36,964.84) 227.36,964.84 ; 227.36,964.84 cw(c227.36,964.84) 227.36,964.84 ; 227.36,964.84 266.73,964.84 ; 227.36,964.84 266.73,964.84 ; 266.73,964.84 ccw(c266.73,964.84) 266.73,964.84 ; 266.73,964.84 ccw(c266.73,964.84) 266.73,964.84 ; 315.94,923.51 152.58,923.51 152.58,1004.21 178,1004.21 178,984.53 197.98,984.53 197.98,1004.21 217.37,1004.21 217.37,984.53 237.35,984.53 237.35,1004.21 256.74,1004.21 256.74,984.53 276.72,984.53 276.72,1004.21 315.94,1004.21 ; 315.94,923.51 315.94,1004.21 ; 315.94,923.51 315.94,1004.21 ; 315.94,923.51 315.94,1004.21 ; 315.94,923.51 315.94,1004.21 ; 323.82,797.52 323.82,960.88 404.52,960.88 404.52,935.46 384.84,935.46 384.84,915.49 404.52,915.49 404.52,896.09 384.84,896.09 384.84,876.12 404.52,876.12 404.52,856.72 384.84,856.72 384.84,836.75 404.52,836.75 404.52,797.52 ; 323.82,797.52 323.82,962.87 ; 323.82,797.52 323.82,962.87 ; 323.82,797.52 323.82,962.87 ; 323.82,797.52 404.52,797.52 ; 323.82,797.52 404.52,797.52 ; 323.82,797.52 404.52,797.52 ; 323.82,797.52 404.52,797.52 ; 323.82,962.87 365.15,962.87 ; 323.82,962.87 404.52,962.87 ; 323.82,962.87 404.52,962.87 ; 365.15,846.74 ccw(c365.15,846.73) 365.16,846.73 ; 365.16,846.73 ccw(c365.15,846.73) 365.15,846.74 ; 365.15,846.74 365.15,886.1 ; 365.15,846.74 365.15,886.1 ; 365.15,886.11 ccw(c365.15,886.1) 365.15,886.1 ; 365.15,886.1 ccw(c365.15,886.1) 365.16,886.1 ; 365.16,886.1 ccw(c365.15,886.1) 365.15,886.11 ; 365.15,886.11 365.15,925.47 ; 365.15,886.11 365.15,925.47 ; 365.15,925.47 cw(c365.15,925.47) 365.15,925.48 ; 365.16,925.47 ccw(c365.15,925.47) 365.15,925.48 ; 365.15,925.47 ccw(c365.15,925.47) 365.16,925.47 ; 365.15,925.48 365.15,962.87 ; 365.15,925.48 365.15,962.87 ; 365.15,962.87 404.52,962.87 ; 404.52,797.52 323.43,797.52 323.43,962.87 404.52,962.87 ; 404.52,797.52 404.52,962.87 ; 404.52,797.52 404.52,962.87 ; 404.52,797.52 404.52,962.87 ; 404.52,797.52 404.52,962.87 ; 134.05,915.01 134.05,1012.32 332.48,1012.32 332.48,915.01 134.05,915.01 ; 183.34,966.46 ccw(c187.99,964.84) 192.64,966.44 192.64,1004.21 183.34,1004.21 183.34,966.46 ; 222.71,966.46 ccw(c227.36,964.84) 232.01,966.44 232.01,1004.21 222.71,1004.21 222.71,966.46 ; 262.08,966.46 ccw(c266.73,964.84) 271.38,966.44 271.38,1004.21 262.08,1004.21 262.08,966.46 ; 315.32,780.98 315.32,979.41 412.63,979.41 412.63,780.98 315.32,780.98 ; 366.75,842.08 cw(c365.15,846.74) 366.78,851.38 404.52,851.38 404.52,842.08 366.75,842.08 ; 366.75,881.45 cw(c365.15,886.11) 366.78,890.75 404.52,890.75 404.52,881.45 366.75,881.45 ; 366.75,920.82 cw(c365.15,925.48) 366.78,930.12 404.52,930.12 404.52,920.83 366.75,920.82

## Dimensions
-112.62,1632.75 to -112.62,0 on M2 Board Dimensions
0,1720.25 to 858.22,1720.25 on M2 Board Dimensions
0,1632.75 to 0,0 on M2 Board Dimensions
0,1632.75 to 858.22,1632.75 on M2 Board Dimensions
